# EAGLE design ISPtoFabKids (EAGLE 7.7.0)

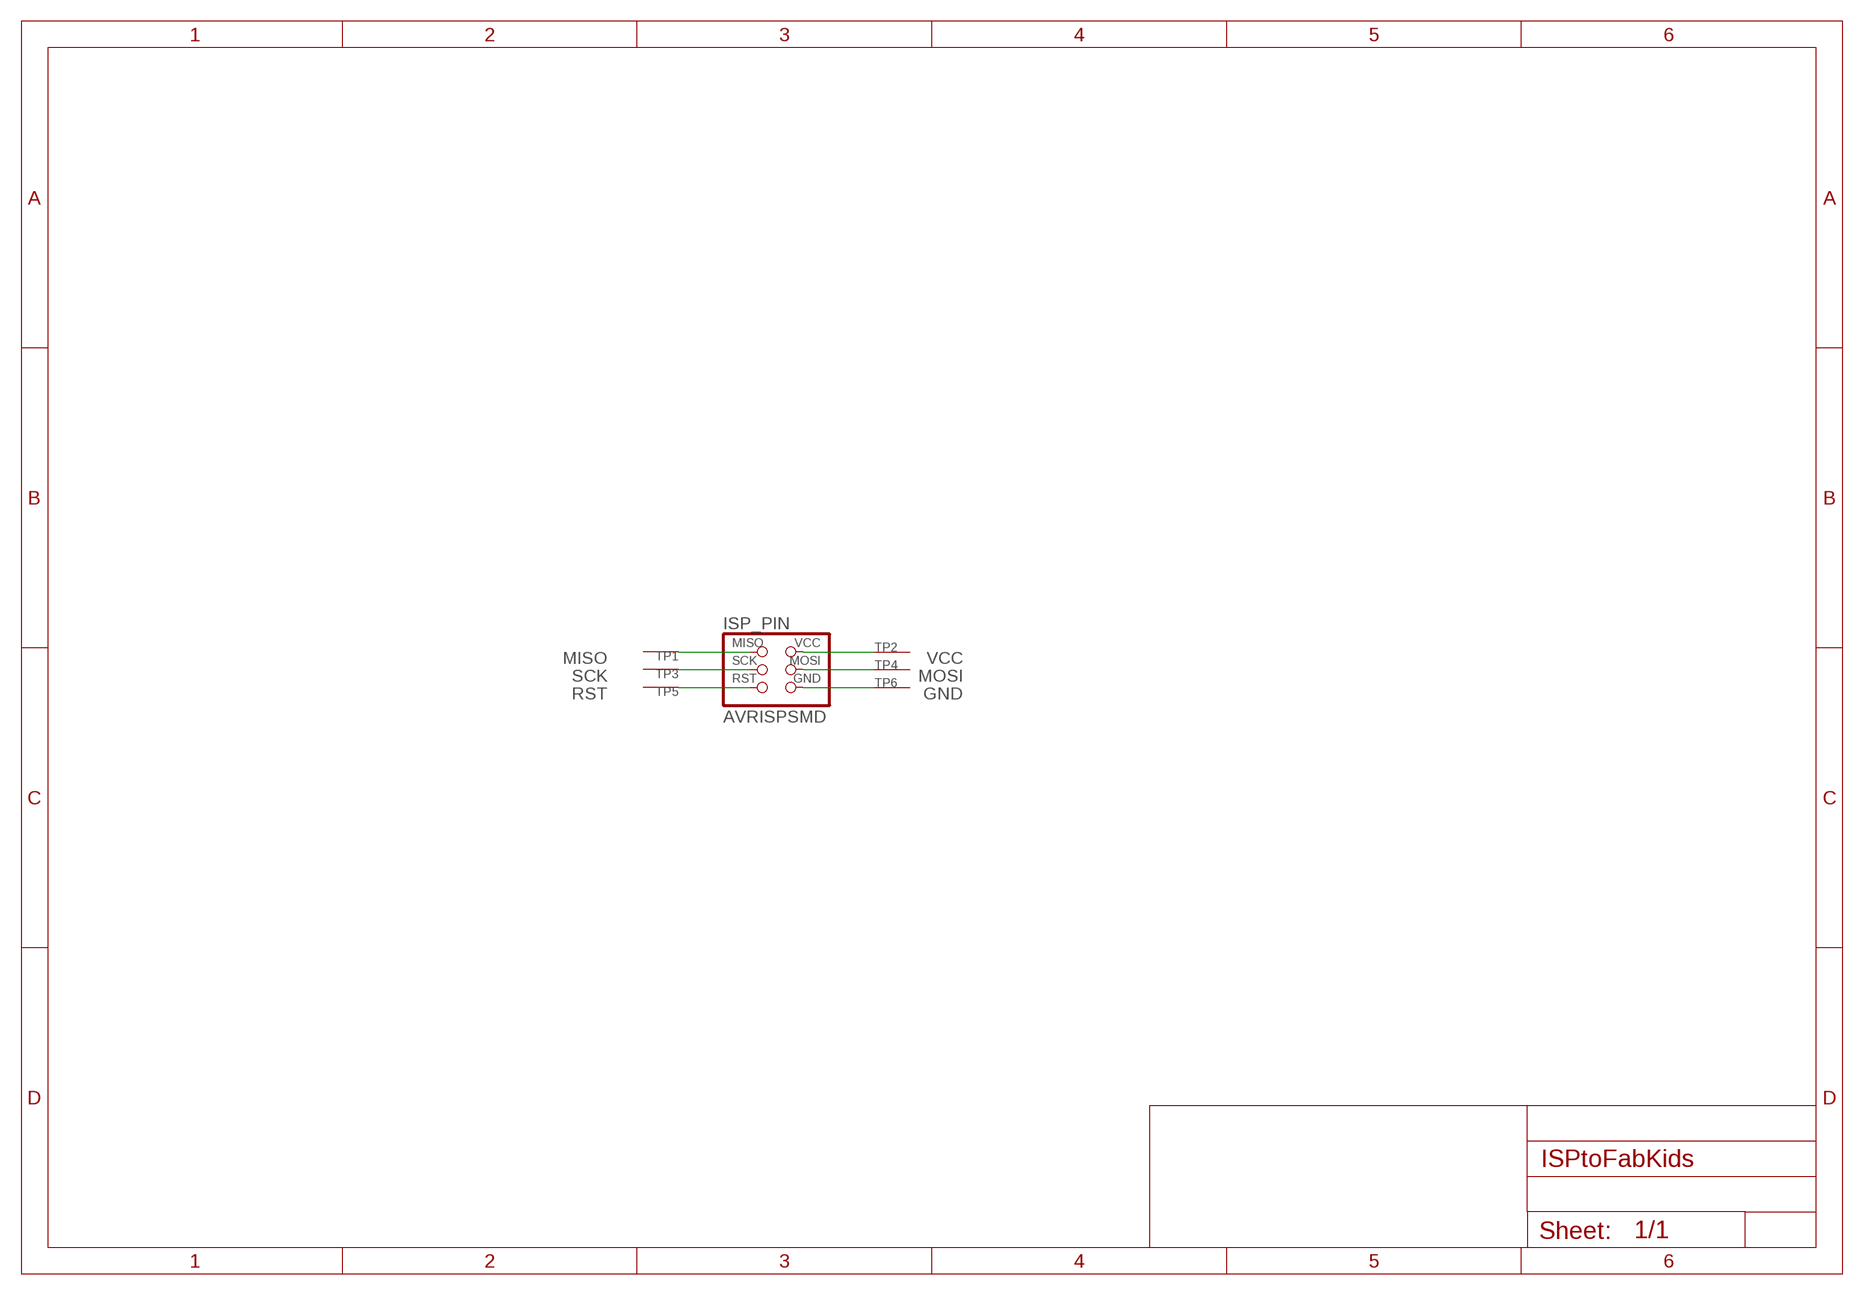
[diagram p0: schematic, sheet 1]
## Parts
ISP_PIN  AVRISPSMD  [2X03SMD]
TP1  SEWTAPBIG  [BIGTAP]
TP2  SEWTAPBIG  [BIGTAP]
TP3  SEWTAPBIG  [BIGTAP]
TP4  SEWTAPBIG  [BIGTAP]
TP5  SEWTAPBIG  [BIGTAP]
TP6  SEWTAPBIG  [BIGTAP]

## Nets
GND: ISP_PIN.6(GND) TP6.P$1(SEW)
MISO: ISP_PIN.1(MISO) TP1.P$1(SEW)
MOSI: ISP_PIN.4(MOSI) TP4.P$1(SEW)
RST: ISP_PIN.5(RST) TP5.P$1(SEW)
SCK: ISP_PIN.3(SCK) TP3.P$1(SEW)
VCC: ISP_PIN.2(VCC) TP2.P$1(SEW)

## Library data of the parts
ISP_PIN = fab:AVRISP
TP1-TP6 = adafruit:SEWTAP

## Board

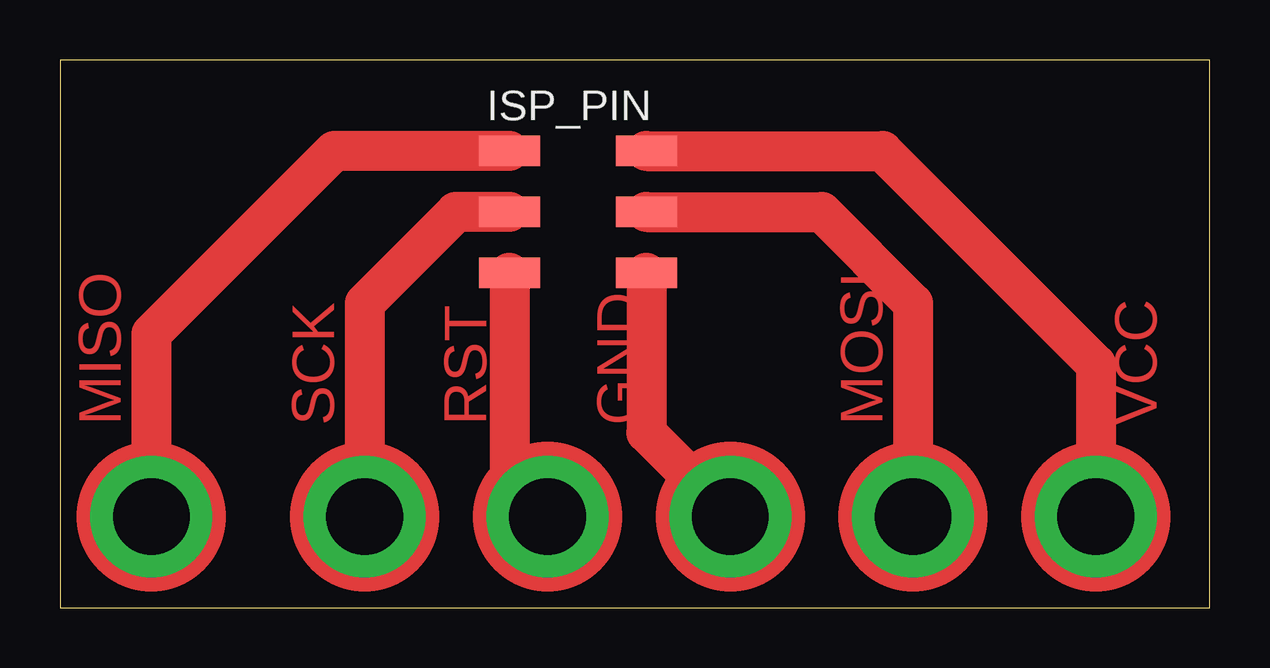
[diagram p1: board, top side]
Size 47.93 x 22.85 mm. Coordinates in mm from the lower left corner, seen from the top.
Outline: 0,0 47.93,0 47.93,22.85 0,22.85 0,0
Copper layers (1*16): Top 0.035mm / dielectric 1.5mm / Bottom 0.035mm
Design rules "default *": minimum track width 10mil, minimum drill 24mil, track to track 0.4046mm, track to pad 0.154240625mm, pad to pad 0.154240625mm, via to via 0.154240625mm, smd to smd 0.154240625mm, copper to edge 40mil, drill to drill 8mil, minimum pad ring 10mil, minimum via ring 8mil, stop-mask expansion 4mil, vias tented up to drill 0mil, thermal gap 10mil

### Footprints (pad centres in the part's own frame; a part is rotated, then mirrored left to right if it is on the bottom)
2X03SMD = smd 2.54 x 1.27: 1 -2.857,2.54; 2 2.857,2.54; 3 -2.857,0; 4 2.857,0; 5 -2.857,-2.54; 6 2.857,-2.54
BIGTAP = drill 3.2 pad 5.08: P$1 0,0

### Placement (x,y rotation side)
ISP_PIN  21.59,16.51 0 top
TP1  3.81,3.81 0 top
TP2  43.18,3.81 0 top
TP3  12.7,3.81 0 top
TP4  35.56,3.81 0 top
TP5  20.32,3.81 0 top
TP6  27.94,3.81 0 top

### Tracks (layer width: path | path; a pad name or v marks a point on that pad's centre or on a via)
GND
  Top 1.676: ISP_PIN.6 24.45,7.3 TP6.P$1
MISO
  Top 1.676: ISP_PIN.1 11.43,19.05 3.81,11.43 TP1.P$1
MOSI
  Top 1.676: ISP_PIN.4 31.75,16.51 35.56,12.7 TP4.P$1
RST
  Top 1.676: ISP_PIN.5 18.73,5.4 TP5.P$1
SCK
  Top 1.676: ISP_PIN.3 16.51,16.51 12.7,12.7 TP3.P$1
VCC
  Top 1.676: ISP_PIN.2 34.29,19.05 43.18,10.16 TP2.P$1

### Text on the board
Top: MISO | SCK | RST | GND | MOSI | VCC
